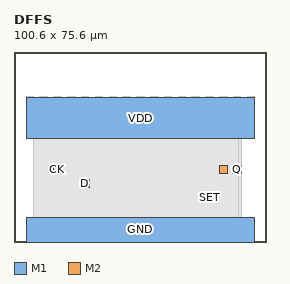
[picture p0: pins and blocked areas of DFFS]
MACRO DFFS
  CLASS CORE ;
  ORIGIN 0 0 ;
  SIZE 100.600 BY 75.600 ;
  SYMMETRY X Y ;
  SITE TR1um_access_site ;
  PIN VDD
    DIRECTION INOUT ;
    USE POWER ;
    PORT
      LAYER M1 ;
        RECT 5.000 41.000 95.600 57.600 ;
    END
  END VDD
  PIN GND
    DIRECTION INOUT ;
    USE GROUND ;
    PORT
      LAYER M1 ;
        RECT 5.000 0.000 95.600 9.800 ;
    END
  END GND
  PIN CK
    DIRECTION INPUT ;
    USE SIGNAL ;
    PORT
      LAYER M2 ;
        RECT 15.600 27.100 19.000 30.500 ;
    END
  END CK
  PIN D
    DIRECTION INPUT ;
    USE SIGNAL ;
    PORT
      LAYER M2 ;
        RECT 26.500 21.600 29.900 25.000 ;
    END
  END D
  PIN Q
    DIRECTION OUTPUT ;
    USE SIGNAL ;
    PORT
      LAYER M2 ;
        RECT 87.100 27.100 90.500 30.500 ;
    END
  END Q
  PIN QB
    DIRECTION OUTPUT ;
    USE SIGNAL ;
    PORT
      LAYER M2 ;
        RECT 81.600 27.100 85.000 30.500 ;
    END
  END QB
  PIN SET
    DIRECTION INPUT ;
    USE SIGNAL ;
    PORT
      LAYER M2 ;
        RECT 76.100 16.100 79.500 19.500 ;
    END
  END SET
  OBS
    LAYER M1 ;
      RECT 76.100 16.100 79.500 22.750 ;
    LAYER M1 ;
      RECT 39.500 15.200 42.100 29.200 ;
    LAYER M1 ;
      RECT 59.900 15.200 62.500 31.600 ;
    LAYER M1 ;
      RECT 26.300 15.200 30.000 35.600 ;
    LAYER M1 ;
      RECT 49.000 17.600 51.600 35.600 ;
    LAYER M1 ;
      RECT 55.100 15.200 64.100 35.600 ;
    LAYER M1 ;
      RECT 13.100 13.600 19.000 37.200 ;
    LAYER M1 ;
      RECT 9.100 6.400 11.700 51.200 ;
    LAYER M1 ;
      RECT 17.100 6.400 24.900 51.200 ;
    LAYER M1 ;
      RECT 21.100 6.400 34.000 51.200 ;
    LAYER M1 ;
      RECT 31.500 6.400 43.200 51.200 ;
    LAYER M1 ;
      RECT 40.700 6.400 53.700 51.200 ;
    LAYER M1 ;
      RECT 58.700 6.400 70.500 51.200 ;
    LAYER M1 ;
      RECT 69.500 6.400 79.300 51.200 ;
    LAYER M1 ;
      RECT 75.500 6.400 85.000 51.200 ;
    LAYER M1 ;
      RECT 83.500 6.400 90.500 51.200 ;
    LAYER V1 ;
      RECT 4.800 0.000 7.800 2.800 ;
    LAYER V1 ;
      RECT 10.300 0.000 13.300 2.800 ;
    LAYER V1 ;
      RECT 15.800 0.000 18.800 2.800 ;
    LAYER V1 ;
      RECT 21.300 0.000 24.300 2.800 ;
    LAYER V1 ;
      RECT 26.800 0.000 29.800 2.800 ;
    LAYER V1 ;
      RECT 32.300 0.000 35.300 2.800 ;
    LAYER V1 ;
      RECT 37.800 0.000 40.800 2.800 ;
    LAYER V1 ;
      RECT 43.300 0.000 46.300 2.800 ;
    LAYER V1 ;
      RECT 48.800 0.000 51.800 2.800 ;
    LAYER V1 ;
      RECT 54.300 0.000 57.300 2.800 ;
    LAYER V1 ;
      RECT 59.800 0.000 62.800 2.800 ;
    LAYER V1 ;
      RECT 65.300 0.000 68.300 2.800 ;
    LAYER V1 ;
      RECT 70.800 0.000 73.800 2.800 ;
    LAYER V1 ;
      RECT 76.300 0.000 79.300 2.800 ;
    LAYER V1 ;
      RECT 81.800 0.000 84.800 2.800 ;
    LAYER V1 ;
      RECT 87.300 0.000 90.300 2.800 ;
    LAYER V1 ;
      RECT 92.800 0.000 95.800 2.800 ;
    LAYER V1 ;
      RECT 77.100 17.100 78.500 18.500 ;
    LAYER V1 ;
      RECT 27.500 22.600 28.900 24.000 ;
    LAYER V1 ;
      RECT 82.600 28.100 84.000 29.500 ;
    LAYER V1 ;
      RECT 88.100 28.100 89.500 29.500 ;
    LAYER V1 ;
      RECT 7.900 4.000 89.500 53.600 ;
    LAYER V1 ;
      RECT 4.800 54.800 7.800 57.800 ;
    LAYER V1 ;
      RECT 10.300 54.800 13.300 57.800 ;
    LAYER V1 ;
      RECT 15.800 54.800 18.800 57.800 ;
    LAYER V1 ;
      RECT 21.300 54.800 24.300 57.800 ;
    LAYER V1 ;
      RECT 26.800 54.800 29.800 57.800 ;
    LAYER V1 ;
      RECT 32.300 54.800 35.300 57.800 ;
    LAYER V1 ;
      RECT 37.800 54.800 40.800 57.800 ;
    LAYER V1 ;
      RECT 43.300 54.800 46.300 57.800 ;
    LAYER V1 ;
      RECT 48.800 54.800 51.800 57.800 ;
    LAYER V1 ;
      RECT 54.300 54.800 57.300 57.800 ;
    LAYER V1 ;
      RECT 59.800 54.800 62.800 57.800 ;
    LAYER V1 ;
      RECT 65.300 54.800 68.300 57.800 ;
    LAYER V1 ;
      RECT 70.800 54.800 73.800 57.800 ;
    LAYER V1 ;
      RECT 76.300 54.800 79.300 57.800 ;
    LAYER V1 ;
      RECT 81.800 54.800 84.800 57.800 ;
    LAYER V1 ;
      RECT 87.300 54.800 90.300 57.800 ;
    LAYER V1 ;
      RECT 92.800 54.800 95.800 57.800 ;
  END
END DFFS
